<?xml version="1.0" encoding="utf-8"?>
<device schemaVersion="1.1" xmlns:xs="http://www.w3.org/2001/XMLSchema-instance" xs:noNamespaceSchemaLocation="CMSIS-SVD.xsd">
  <vendor>Fictional</vendor>
  <name>TBMCU001</name>
  <description>Fictional MCU for PAC Generation</description>
  <addressUnitBits>8</addressUnitBits>
  <width>32</width>
  <size>32</size>
  <resetValue>0x00000000</resetValue>
  <resetMask>0xFFFFFFFF</resetMask>

  <peripherals>
    <!-- GPIO Port A -->
    <peripheral>
      <name>GPIOA</name>
      <description>General Purpose I/O Port A</description>
      <baseAddress>0x40005000</baseAddress>
      <registers>
        <register>
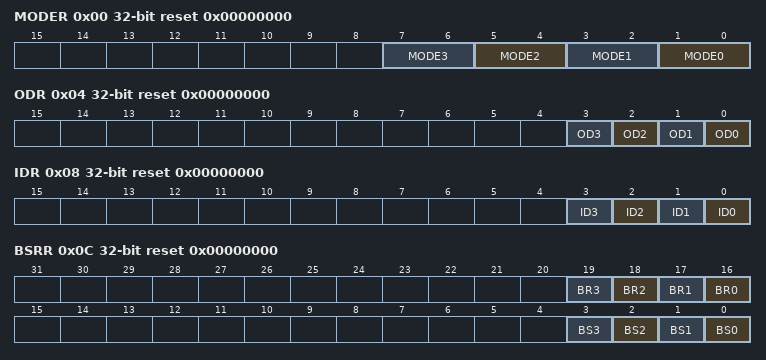
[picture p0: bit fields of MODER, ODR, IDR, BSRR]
          <name>MODER</name>
          <description>Port mode register</description>
          <addressOffset>0x00</addressOffset>
          <size>32</size>
          <access>read-write</access>
          <resetValue>0x00000000</resetValue>
          <fields>
            <field>
              <name>MODE0</name>
              <description>Pin 0 mode</description>
              <bitOffset>0</bitOffset>
              <bitWidth>2</bitWidth>
              <enumeratedValues>
                <enumeratedValue><name>Input</name><value>0</value></enumeratedValue>
                <enumeratedValue><name>Output</name><value>1</value></enumeratedValue>
                <enumeratedValue><name>Alternate</name><value>2</value></enumeratedValue>
                <enumeratedValue><name>Analog</name><value>3</value></enumeratedValue>
              </enumeratedValues>
            </field>
            <field>
              <name>MODE1</name>
              <description>Pin 1 mode</description>
              <bitOffset>2</bitOffset>
              <bitWidth>2</bitWidth>
              <enumeratedValues>
                <enumeratedValue><name>Input</name><value>0</value></enumeratedValue>
                <enumeratedValue><name>Output</name><value>1</value></enumeratedValue>
                <enumeratedValue><name>Alternate</name><value>2</value></enumeratedValue>
                <enumeratedValue><name>Analog</name><value>3</value></enumeratedValue>
              </enumeratedValues>
            </field>
            <field>
              <name>MODE2</name>
              <description>Pin 2 mode</description>
              <bitOffset>4</bitOffset>
              <bitWidth>2</bitWidth>
              <enumeratedValues>
                <enumeratedValue><name>Input</name><value>0</value></enumeratedValue>
                <enumeratedValue><name>Output</name><value>1</value></enumeratedValue>
                <enumeratedValue><name>Alternate</name><value>2</value></enumeratedValue>
                <enumeratedValue><name>Analog</name><value>3</value></enumeratedValue>
              </enumeratedValues>
            </field>
            <field>
              <name>MODE3</name>
              <description>Pin 3 mode</description>
              <bitOffset>6</bitOffset>
              <bitWidth>2</bitWidth>
              <enumeratedValues>
                <enumeratedValue><name>Input</name><value>0</value></enumeratedValue>
                <enumeratedValue><name>Output</name><value>1</value></enumeratedValue>
                <enumeratedValue><name>Alternate</name><value>2</value></enumeratedValue>
                <enumeratedValue><name>Analog</name><value>3</value></enumeratedValue>
              </enumeratedValues>
            </field>
          </fields>
        </register>

        <register>
          <name>ODR</name>
          <description>Output data register</description>
          <addressOffset>0x04</addressOffset>
          <size>32</size>
          <access>read-write</access>
          <resetValue>0x00000000</resetValue>
          <fields>
            <field><name>OD0</name><description>Output bit 0</description><bitOffset>0</bitOffset><bitWidth>1</bitWidth></field>
            <field><name>OD1</name><description>Output bit 1</description><bitOffset>1</bitOffset><bitWidth>1</bitWidth></field>
            <field><name>OD2</name><description>Output bit 2</description><bitOffset>2</bitOffset><bitWidth>1</bitWidth></field>
            <field><name>OD3</name><description>Output bit 3</description><bitOffset>3</bitOffset><bitWidth>1</bitWidth></field>
          </fields>
        </register>

        <register>
          <name>IDR</name>
          <description>Input data register</description>
          <addressOffset>0x08</addressOffset>
          <size>32</size>
          <access>read-only</access>
          <resetValue>0x00000000</resetValue>
          <fields>
            <field><name>ID0</name><description>Input bit 0</description><bitOffset>0</bitOffset><bitWidth>1</bitWidth></field>
            <field><name>ID1</name><description>Input bit 1</description><bitOffset>1</bitOffset><bitWidth>1</bitWidth></field>
            <field><name>ID2</name><description>Input bit 2</description><bitOffset>2</bitOffset><bitWidth>1</bitWidth></field>
            <field><name>ID3</name><description>Input bit 3</description><bitOffset>3</bitOffset><bitWidth>1</bitWidth></field>
          </fields>
        </register>

        <register>
          <name>BSRR</name>
          <description>Bit set/reset register</description>
          <addressOffset>0x0C</addressOffset>
          <size>32</size>
          <access>write-only</access>
          <resetValue>0x00000000</resetValue>
          <fields>
            <field><name>BS0</name><description>Set bit 0</description><bitOffset>0</bitOffset><bitWidth>1</bitWidth></field>
            <field><name>BS1</name><description>Set bit 1</description><bitOffset>1</bitOffset><bitWidth>1</bitWidth></field>
            <field><name>BS2</name><description>Set bit 2</description><bitOffset>2</bitOffset><bitWidth>1</bitWidth></field>
            <field><name>BS3</name><description>Set bit 3</description><bitOffset>3</bitOffset><bitWidth>1</bitWidth></field>
            <field><name>BR0</name><description>Reset bit 0</description><bitOffset>16</bitOffset><bitWidth>1</bitWidth></field>
            <field><name>BR1</name><description>Reset bit 1</description><bitOffset>17</bitOffset><bitWidth>1</bitWidth></field>
            <field><name>BR2</name><description>Reset bit 2</description><bitOffset>18</bitOffset><bitWidth>1</bitWidth></field>
            <field><name>BR3</name><description>Reset bit 3</description><bitOffset>19</bitOffset><bitWidth>1</bitWidth></field>
          </fields>
        </register>
      </registers>
    </peripheral>

    <!-- GPIO Port B: derived from GPIOA with additional AFRL register -->
    <peripheral derivedFrom="GPIOA">
      <name>GPIOB</name>
      <description>General Purpose I/O Port B</description>
      <baseAddress>0x40006000</baseAddress>
      <registers>
        <register>
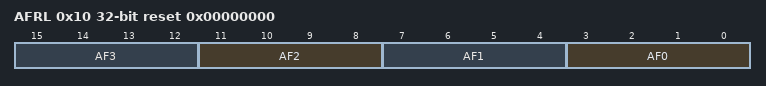
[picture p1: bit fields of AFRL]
          <name>AFRL</name>
          <description>Alternate function low register</description>
          <addressOffset>0x10</addressOffset>
          <size>32</size>
          <access>read-write</access>
          <resetValue>0x00000000</resetValue>
          <fields>
            <field><name>AF0</name><description>Pin 0 alternate function</description><bitOffset>0</bitOffset><bitWidth>4</bitWidth></field>
            <field><name>AF1</name><description>Pin 1 alternate function</description><bitOffset>4</bitOffset><bitWidth>4</bitWidth></field>
            <field><name>AF2</name><description>Pin 2 alternate function</description><bitOffset>8</bitOffset><bitWidth>4</bitWidth></field>
            <field><name>AF3</name><description>Pin 3 alternate function</description><bitOffset>12</bitOffset><bitWidth>4</bitWidth></field>
          </fields>
        </register>
      </registers>
    </peripheral>

    <!-- SPI1 -->
    <peripheral>
      <name>SPI1</name>
      <description>Serial Peripheral Interface</description>
      <baseAddress>0x40008000</baseAddress>
      <registers>
        <register>
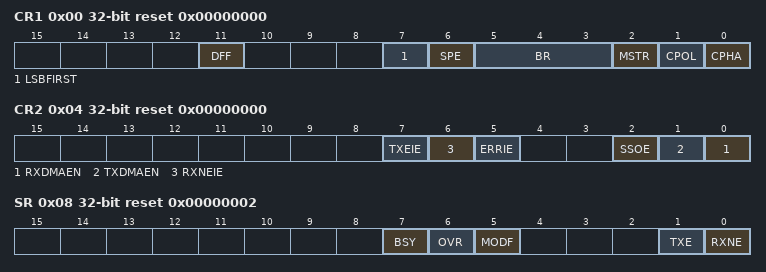
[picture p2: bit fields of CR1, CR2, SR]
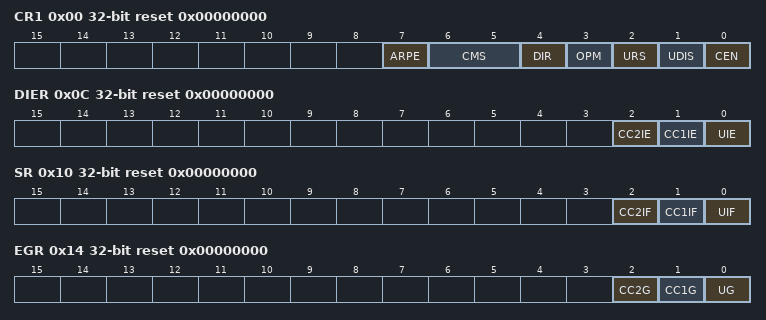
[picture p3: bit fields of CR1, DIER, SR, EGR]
          <name>CR1</name>
          <description>Control register 1</description>
          <addressOffset>0x00</addressOffset>
          <size>32</size>
          <access>read-write</access>
          <resetValue>0x00000000</resetValue>
          <fields>
            <field>
              <name>CPHA</name><description>Clock phase</description>
              <bitOffset>0</bitOffset><bitWidth>1</bitWidth>
              <enumeratedValues>
                <enumeratedValue><name>FirstEdge</name><value>0</value></enumeratedValue>
                <enumeratedValue><name>SecondEdge</name><value>1</value></enumeratedValue>
              </enumeratedValues>
            </field>
            <field>
              <name>CPOL</name><description>Clock polarity</description>
              <bitOffset>1</bitOffset><bitWidth>1</bitWidth>
              <enumeratedValues>
                <enumeratedValue><name>IdleLow</name><value>0</value></enumeratedValue>
                <enumeratedValue><name>IdleHigh</name><value>1</value></enumeratedValue>
              </enumeratedValues>
            </field>
            <field>
              <name>MSTR</name><description>Master selection</description>
              <bitOffset>2</bitOffset><bitWidth>1</bitWidth>
              <enumeratedValues>
                <enumeratedValue><name>Slave</name><value>0</value></enumeratedValue>
                <enumeratedValue><name>Master</name><value>1</value></enumeratedValue>
              </enumeratedValues>
            </field>
            <field>
              <name>BR</name><description>Baud rate prescaler</description>
              <bitOffset>3</bitOffset><bitWidth>3</bitWidth>
              <enumeratedValues>
                <enumeratedValue><name>Div2</name><value>0</value></enumeratedValue>
                <enumeratedValue><name>Div4</name><value>1</value></enumeratedValue>
                <enumeratedValue><name>Div8</name><value>2</value></enumeratedValue>
                <enumeratedValue><name>Div16</name><value>3</value></enumeratedValue>
                <enumeratedValue><name>Div32</name><value>4</value></enumeratedValue>
                <enumeratedValue><name>Div64</name><value>5</value></enumeratedValue>
                <enumeratedValue><name>Div128</name><value>6</value></enumeratedValue>
                <enumeratedValue><name>Div256</name><value>7</value></enumeratedValue>
              </enumeratedValues>
            </field>
            <field><name>SPE</name><description>SPI enable</description><bitOffset>6</bitOffset><bitWidth>1</bitWidth></field>
            <field>
              <name>LSBFIRST</name><description>Frame format</description>
              <bitOffset>7</bitOffset><bitWidth>1</bitWidth>
              <enumeratedValues>
                <enumeratedValue><name>MsbFirst</name><value>0</value></enumeratedValue>
                <enumeratedValue><name>LsbFirst</name><value>1</value></enumeratedValue>
              </enumeratedValues>
            </field>
            <field>
              <name>DFF</name><description>Data frame format</description>
              <bitOffset>11</bitOffset><bitWidth>1</bitWidth>
              <enumeratedValues>
                <enumeratedValue><name>Eight</name><value>0</value></enumeratedValue>
                <enumeratedValue><name>Sixteen</name><value>1</value></enumeratedValue>
              </enumeratedValues>
            </field>
          </fields>
        </register>

        <register>
          <name>CR2</name>
          <description>Control register 2</description>
          <addressOffset>0x04</addressOffset>
          <size>32</size>
          <access>read-write</access>
          <resetValue>0x00000000</resetValue>
          <fields>
            <field><name>RXDMAEN</name><description>RX DMA enable</description><bitOffset>0</bitOffset><bitWidth>1</bitWidth></field>
            <field><name>TXDMAEN</name><description>TX DMA enable</description><bitOffset>1</bitOffset><bitWidth>1</bitWidth></field>
            <field><name>SSOE</name><description>SS output enable</description><bitOffset>2</bitOffset><bitWidth>1</bitWidth></field>
            <field><name>ERRIE</name><description>Error interrupt enable</description><bitOffset>5</bitOffset><bitWidth>1</bitWidth></field>
            <field><name>RXNEIE</name><description>RX not empty interrupt enable</description><bitOffset>6</bitOffset><bitWidth>1</bitWidth></field>
            <field><name>TXEIE</name><description>TX empty interrupt enable</description><bitOffset>7</bitOffset><bitWidth>1</bitWidth></field>
          </fields>
        </register>

        <register>
          <name>SR</name>
          <description>Status register</description>
          <addressOffset>0x08</addressOffset>
          <size>32</size>
          <access>read-only</access>
          <resetValue>0x00000002</resetValue>
          <fields>
            <field><name>RXNE</name><description>Receive not empty</description><bitOffset>0</bitOffset><bitWidth>1</bitWidth></field>
            <field><name>TXE</name><description>Transmit empty</description><bitOffset>1</bitOffset><bitWidth>1</bitWidth></field>
            <field><name>MODF</name><description>Mode fault</description><bitOffset>5</bitOffset><bitWidth>1</bitWidth></field>
            <field><name>OVR</name><description>Overrun</description><bitOffset>6</bitOffset><bitWidth>1</bitWidth></field>
            <field><name>BSY</name><description>Busy flag</description><bitOffset>7</bitOffset><bitWidth>1</bitWidth></field>
          </fields>
        </register>

        <register>
          <name>DR</name>
          <description>Data register</description>
          <addressOffset>0x0C</addressOffset>
          <size>32</size>
          <access>read-write</access>
          <resetValue>0x00000000</resetValue>
          <fields>
            <field><name>DR</name><description>Data value</description><bitOffset>0</bitOffset><bitWidth>16</bitWidth></field>
          </fields>
        </register>
      </registers>
    </peripheral>

    <!-- TIM2: general-purpose timer with dim-expanded CCR registers -->
    <peripheral>
      <name>TIM2</name>
      <description>General-purpose timer</description>
      <baseAddress>0x40000000</baseAddress>
      <registers>
        <register>
          <name>CR1</name>
          <description>Control register 1</description>
          <addressOffset>0x00</addressOffset>
          <size>32</size>
          <access>read-write</access>
          <resetValue>0x00000000</resetValue>
          <fields>
            <field><name>CEN</name><description>Counter enable</description><bitOffset>0</bitOffset><bitWidth>1</bitWidth></field>
            <field><name>UDIS</name><description>Update disable</description><bitOffset>1</bitOffset><bitWidth>1</bitWidth></field>
            <field><name>URS</name><description>Update request source</description><bitOffset>2</bitOffset><bitWidth>1</bitWidth></field>
            <field><name>OPM</name><description>One-pulse mode</description><bitOffset>3</bitOffset><bitWidth>1</bitWidth></field>
            <field>
              <name>DIR</name><description>Direction</description>
              <bitOffset>4</bitOffset><bitWidth>1</bitWidth>
              <enumeratedValues>
                <enumeratedValue><name>Up</name><value>0</value></enumeratedValue>
                <enumeratedValue><name>Down</name><value>1</value></enumeratedValue>
              </enumeratedValues>
            </field>
            <field>
              <name>CMS</name><description>Center-aligned mode</description>
              <bitOffset>5</bitOffset><bitWidth>2</bitWidth>
              <enumeratedValues>
                <enumeratedValue><name>EdgeAligned</name><value>0</value></enumeratedValue>
                <enumeratedValue><name>CenterAligned1</name><value>1</value></enumeratedValue>
                <enumeratedValue><name>CenterAligned2</name><value>2</value></enumeratedValue>
                <enumeratedValue><name>CenterAligned3</name><value>3</value></enumeratedValue>
              </enumeratedValues>
            </field>
            <field><name>ARPE</name><description>Auto-reload preload enable</description><bitOffset>7</bitOffset><bitWidth>1</bitWidth></field>
          </fields>
        </register>

        <register>
          <name>DIER</name>
          <description>Interrupt enable register</description>
          <addressOffset>0x0C</addressOffset>
          <size>32</size>
          <access>read-write</access>
          <resetValue>0x00000000</resetValue>
          <fields>
            <field><name>UIE</name><description>Update interrupt enable</description><bitOffset>0</bitOffset><bitWidth>1</bitWidth></field>
            <field><name>CC1IE</name><description>Capture/Compare 1 interrupt enable</description><bitOffset>1</bitOffset><bitWidth>1</bitWidth></field>
            <field><name>CC2IE</name><description>Capture/Compare 2 interrupt enable</description><bitOffset>2</bitOffset><bitWidth>1</bitWidth></field>
          </fields>
        </register>

        <register>
          <name>SR</name>
          <description>Status register</description>
          <addressOffset>0x10</addressOffset>
          <size>32</size>
          <access>read-write</access>
          <resetValue>0x00000000</resetValue>
          <fields>
            <field><name>UIF</name><description>Update interrupt flag</description><bitOffset>0</bitOffset><bitWidth>1</bitWidth></field>
            <field><name>CC1IF</name><description>Capture/Compare 1 flag</description><bitOffset>1</bitOffset><bitWidth>1</bitWidth></field>
            <field><name>CC2IF</name><description>Capture/Compare 2 flag</description><bitOffset>2</bitOffset><bitWidth>1</bitWidth></field>
          </fields>
        </register>

        <register>
          <name>EGR</name>
          <description>Event generation register</description>
          <addressOffset>0x14</addressOffset>
          <size>32</size>
          <access>write-only</access>
          <resetValue>0x00000000</resetValue>
          <fields>
            <field><name>UG</name><description>Update generation</description><bitOffset>0</bitOffset><bitWidth>1</bitWidth></field>
            <field><name>CC1G</name><description>Capture/Compare 1 generation</description><bitOffset>1</bitOffset><bitWidth>1</bitWidth></field>
            <field><name>CC2G</name><description>Capture/Compare 2 generation</description><bitOffset>2</bitOffset><bitWidth>1</bitWidth></field>
          </fields>
        </register>

        <register>
          <name>CNT</name>
          <description>Counter value</description>
          <addressOffset>0x24</addressOffset>
          <size>32</size>
          <access>read-write</access>
          <resetValue>0x00000000</resetValue>
          <fields>
            <field><name>CNT</name><description>Counter value</description><bitOffset>0</bitOffset><bitWidth>32</bitWidth></field>
          </fields>
        </register>

        <register>
          <name>PSC</name>
          <description>Prescaler</description>
          <addressOffset>0x28</addressOffset>
          <size>32</size>
          <access>read-write</access>
          <resetValue>0x00000000</resetValue>
          <fields>
            <field><name>PSC</name><description>Prescaler value</description><bitOffset>0</bitOffset><bitWidth>16</bitWidth></field>
          </fields>
        </register>

        <register>
          <name>ARR</name>
          <description>Auto-reload register</description>
          <addressOffset>0x2C</addressOffset>
          <size>32</size>
          <access>read-write</access>
          <resetValue>0x0000FFFF</resetValue>
          <fields>
            <field><name>ARR</name><description>Auto-reload value</description><bitOffset>0</bitOffset><bitWidth>32</bitWidth></field>
          </fields>
        </register>

        <!-- Capture/compare register array using dim -->
        <register>
          <dim>4</dim>
          <dimIncrement>0x4</dimIncrement>
          <dimIndex>1-4</dimIndex>
          <name>CCR%s</name>
          <description>Capture/compare register %s</description>
          <addressOffset>0x34</addressOffset>
          <size>32</size>
          <access>read-write</access>
          <resetValue>0x00000000</resetValue>
          <fields>
            <field><name>CCR</name><description>Capture/compare value</description><bitOffset>0</bitOffset><bitWidth>32</bitWidth></field>
          </fields>
        </register>
      </registers>
    </peripheral>
  </peripherals>
</device>
